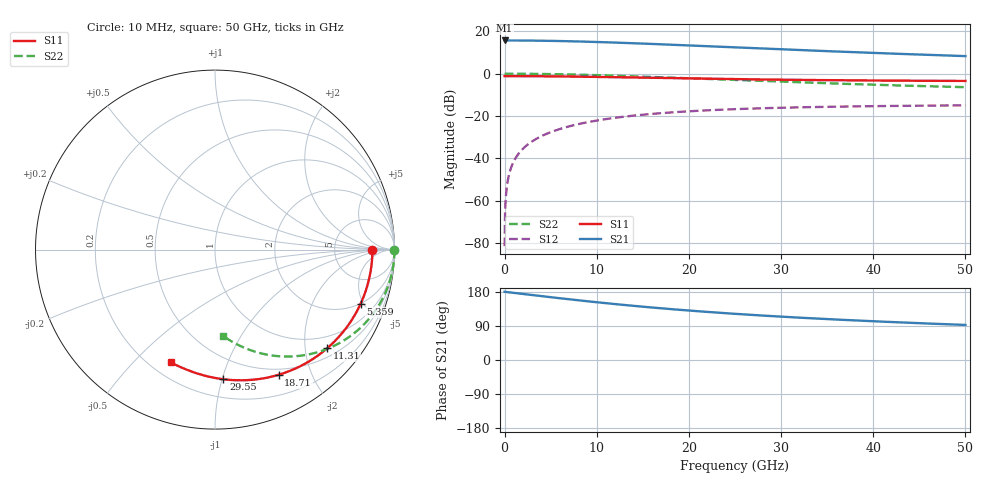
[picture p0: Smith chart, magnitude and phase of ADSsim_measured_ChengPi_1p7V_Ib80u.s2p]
! Created Wed Apr 01 23:55:13 2026
# hz S ma R 50
! 2 Port Network Data from SP1.SP block
! freq  magS11  angS11  magS21  angS21  magS12  angS12  magS22  angS22
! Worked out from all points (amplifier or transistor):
!   1001 points, 10 MHz to 50 GHz, reference 50 ohm
!   highest |S21| = 15.7 dB at 10 MHz (marker M1)
!   |S21| within 3 dB of that: start of sweep to 23.56 GHz
!   unconditionally stable (mu >= 1): nowhere
!   at 8.308 GHz: K = 0.08, MSG = 19.3 dB, |S12| = -23.5 dB
!   at 25 GHz: K = 0.24, MSG = 14.6 dB, |S12| = -16.7 dB
!   at 50 GHz: K = 0.48, MSG = 11.6 dB, |S12| = -14.9 dB
!   S11 on the Smith chart (normalised r, x): 10 MHz: 15, -0; 5.359 GHz: 1.97, -4.75; 11.31 GHz: 0.69, -2.48; 18.71 GHz: 0.43, -1.55; 29.55 GHz: 0.33, -1.01; 50 GHz: 0.28, -0.64
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1e7  0.8771 -0.0  6.09 180.0  8.529e-05 90.0  1 -0.0
3.0994e8  0.8771 -1.2  6.089 179.1  0.002643 89.2  0.9999 -0.9
4.0992e8  0.8771 -1.6  6.089 178.8  0.003495 89.0  0.9999 -1.2
7.0986e8  0.8769 -2.7  6.087 177.9  0.006051 88.2  0.9996 -2.0
1.10978e9  0.8766 -4.3  6.083 176.8  0.009454 87.2  0.999 -3.2
1.80964e9  0.8758 -7.0  6.072 174.8  0.01539 85.4  0.9972 -5.2
2.70946e9  0.8741 -10.5  6.05 172.2  0.02296 83.1  0.9939 -7.7
3.90922e9  0.8709 -15.0  6.008 168.8  0.03289 80.2  0.9874 -11.1
5.35893e9  0.8656 -20.5  5.939 164.7  0.04456 76.6  0.9767 -15.1
8.35833e9  0.8506 -31.3  5.741 156.6  0.06717 69.6  0.9461 -23.1
1.130774e10  0.8323 -41.4  5.493 149.2  0.0869 63.1  0.9079 -30.4
1.395721e10  0.8144 -49.7  5.243 143.0  0.1023 57.8  0.8696 -36.5
1.670666e10  0.7956 -57.7  4.972 137.0  0.1161 52.8  0.8282 -42.4
1.870626e10  0.7824 -63.0  4.774 133.0  0.1248 49.5  0.7981 -46.3
2.165567e10  0.764 -70.3  4.489 127.5  0.1357 45.0  0.7549 -51.7
2.5005e10  0.7453 -77.6  4.182 121.8  0.1458 40.5  0.7088 -57.2
2.955409e10  0.7239 -86.3  3.802 115.0  0.1564 35.3  0.6524 -63.8
3.335333e10  0.7096 -92.4  3.52 110.0  0.1632 31.6  0.6109 -68.6
3.735253e10  0.6975 -98.1  3.255 105.2  0.1687 28.1  0.5725 -73.2
4.170166e10  0.6873 -103.3  3.002 100.5  0.1733 24.9  0.5364 -77.6
4.585083e10  0.6801 -107.7  2.79 96.3  0.1766 22.2  0.5066 -81.5
5e10  0.6749 -111.4  2.602 92.5  0.1792 19.8  0.4808 -85.0
